VERSION 5.7 ;
  NOWIREEXTENSIONATPIN ON ;
  DIVIDERCHAR "/" ;
  BUSBITCHARS "[]" ;
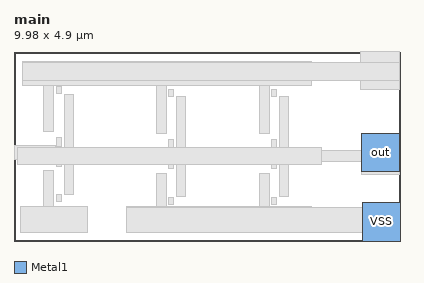
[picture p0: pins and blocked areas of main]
MACRO main
  CLASS BLOCK ;
  FOREIGN main ;
  ORIGIN 1.900 0.300 ;
  SIZE 9.980 BY 4.900 ;
  PIN out
    ANTENNADIFFAREA 0.632400 ;
    PORT
      LAYER Metal1 ;
        RECT 7.050 1.480 8.050 2.480 ;
    END
  END out
  PIN VSS
    USE GROUND ;
    PORT
      LAYER Metal1 ;
        RECT 7.080 -0.300 8.080 0.700 ;
    END
  END VSS
  OBS
      LAYER GatPoly ;
        RECT -0.810 3.495 -0.680 3.675 ;
        RECT 2.090 3.435 2.220 3.615 ;
        RECT 4.750 3.435 4.880 3.615 ;
        RECT -0.810 2.150 -0.680 2.375 ;
        RECT -1.150 1.820 -0.680 2.150 ;
        RECT 2.090 2.090 2.220 2.315 ;
        RECT 4.750 2.090 4.880 2.315 ;
        RECT -0.810 1.630 -0.680 1.820 ;
        RECT 1.750 1.760 2.220 2.090 ;
        RECT 4.410 1.760 4.880 2.090 ;
        RECT 2.090 1.570 2.220 1.760 ;
        RECT 4.750 1.570 4.880 1.760 ;
        RECT -0.810 0.710 -0.680 0.890 ;
        RECT 2.090 0.650 2.220 0.830 ;
        RECT 4.750 0.650 4.880 0.830 ;
      LAYER Metal1 ;
        RECT -1.690 4.300 5.770 4.330 ;
        RECT 7.040 4.300 8.040 4.600 ;
        RECT -1.690 3.830 8.040 4.300 ;
        RECT -1.690 3.720 5.770 3.830 ;
        RECT -1.130 2.535 -0.870 3.720 ;
        RECT -1.900 1.800 -0.820 2.160 ;
        RECT -0.605 2.120 -0.375 3.475 ;
        RECT 1.770 2.475 2.030 3.720 ;
        RECT 2.295 2.120 2.525 3.415 ;
        RECT 4.430 2.475 4.690 3.720 ;
        RECT 7.040 3.600 8.040 3.830 ;
        RECT -0.605 2.090 2.050 2.120 ;
        RECT 2.295 2.090 4.720 2.120 ;
        RECT -0.605 1.790 2.065 2.090 ;
        RECT -1.130 0.590 -0.870 1.510 ;
        RECT -0.605 0.910 -0.375 1.790 ;
        RECT 1.750 1.760 2.065 1.790 ;
        RECT 2.295 1.760 4.725 2.090 ;
        RECT 4.955 2.040 5.185 3.415 ;
        RECT 4.955 1.760 7.050 2.040 ;
        RECT 2.295 1.720 4.720 1.760 ;
        RECT 1.770 0.590 2.030 1.450 ;
        RECT 2.295 0.850 2.525 1.720 ;
        RECT 4.430 0.590 4.690 1.450 ;
        RECT 4.955 0.850 5.185 1.760 ;
        RECT 7.050 1.410 8.050 1.480 ;
        RECT -1.740 -0.070 0.000 0.590 ;
        RECT 1.000 0.560 5.770 0.590 ;
        RECT 1.000 -0.070 7.080 0.560 ;
      LAYER Metal2 ;
        RECT -1.810 1.680 6.030 2.120 ;
  END
END main
END LIBRARY

